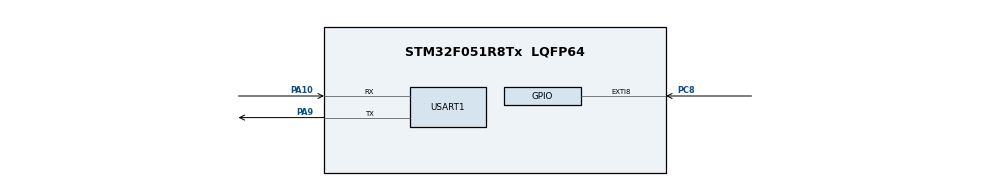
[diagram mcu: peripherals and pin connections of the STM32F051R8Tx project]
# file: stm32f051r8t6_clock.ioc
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Mcu.Family=STM32F0
Mcu.Name=STM32F051R8Tx
Mcu.Package=LQFP64
PA10.Mode=Asynchronous
PA10.Signal=USART1_RX
PA9.Mode=Asynchronous
PA9.Signal=USART1_TX
PC8.Signal=GPXTI8
ProjectManager.HeapSize=0x200
ProjectManager.StackSize=0x400
ProjectManager.TargetToolchain=MDK-ARM V5
RCC.AHBCLKDivider=RCC_SYSCLK_DIV2
RCC.AHBFreq_Value=8000000
RCC.APB1Freq_Value=8000000
RCC.APB1TimFreq_Value=8000000
RCC.HCLKFreq_Value=8000000
RCC.PLLMUL=RCC_PLL_MUL4
RCC.RCC_MCOSource=RCC_MCO1SOURCE_HSI
RCC.SYSCLKFreq_VALUE=16000000
RCC.SYSCLKSource=RCC_SYSCLKSOURCE_PLLCLK
RCC.Usart1ClockSelection=RCC_USART1CLKSOURCE_HSI
USART1.VirtualMode-Asynchronous=VM_ASYNC
board=custom

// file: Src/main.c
/**
  ******************************************************************************
  * @file           : main.c
  * @brief          : Main program body
  ******************************************************************************
  ** This notice applies to any and all portions of this file
  * that are not between comment pairs USER CODE BEGIN and
  * USER CODE END. Other portions of this file, whether
  * inserted by the user or by software development tools
  * are owned by their respective copyright owners.
  *
  * COPYRIGHT(c) 2018 STMicroelectronics
  *
  * Redistribution and use in source and binary forms, with or without modification,
  * are permitted provided that the following conditions are met:
  *   1. Redistributions of source code must retain the above copyright notice,
  *      this list of conditions and the following disclaimer.
  *   2. Redistributions in binary form must reproduce the above copyright notice,
  *      this list of conditions and the following disclaimer in the documentation
  *      and/or other materials provided with the distribution.
  *   3. Neither the name of STMicroelectronics nor the names of its contributors
  *      may be used to endorse or promote products derived from this software
  *      without specific prior written permission.
  *
  * THIS SOFTWARE IS PROVIDED BY THE COPYRIGHT HOLDERS AND CONTRIBUTORS "AS IS"
  * AND ANY EXPRESS OR IMPLIED WARRANTIES, INCLUDING, BUT NOT LIMITED TO, THE
  * IMPLIED WARRANTIES OF MERCHANTABILITY AND FITNESS FOR A PARTICULAR PURPOSE ARE
  * DISCLAIMED. IN NO EVENT SHALL THE COPYRIGHT HOLDER OR CONTRIBUTORS BE LIABLE
  * FOR ANY DIRECT, INDIRECT, INCIDENTAL, SPECIAL, EXEMPLARY, OR CONSEQUENTIAL
  * DAMAGES (INCLUDING, BUT NOT LIMITED TO, PROCUREMENT OF SUBSTITUTE GOODS OR
  * SERVICES; LOSS OF USE, DATA, OR PROFITS; OR BUSINESS INTERRUPTION) HOWEVER
  * CAUSED AND ON ANY THEORY OF LIABILITY, WHETHER IN CONTRACT, STRICT LIABILITY,
  * OR TORT (INCLUDING NEGLIGENCE OR OTHERWISE) ARISING IN ANY WAY OUT OF THE USE
  * OF THIS SOFTWARE, EVEN IF ADVISED OF THE POSSIBILITY OF SUCH DAMAGE.
  *
  ******************************************************************************
  */
#include "main.h"
#include "stm32f0xx_hal.h"

UART_HandleTypeDef huart1;

/* USER CODE BEGIN PV */
/* Private variables ---------------------------------------------------------*/

/* USER CODE END PV */

void SystemClock_Config(void);
static void MX_GPIO_Init(void);
static void MX_USART1_UART_Init(void);

/* USER CODE BEGIN PFP */
/* Private function prototypes -----------------------------------------------*/

/* USER CODE END PFP */

int main(void)
{

  /* MCU Configuration----------------------------------------------------------*/

  /* Reset of all peripherals, Initializes the Flash interface and the Systick. */
  HAL_Init();

  /* Configure the system clock */
  SystemClock_Config();

  /* Initialize all configured peripherals */
  MX_GPIO_Init();
  MX_USART1_UART_Init();

  /* Infinite loop */
  while (1)
  {

  }

}

void SystemClock_Config(void)
{

  RCC_OscInitTypeDef RCC_OscInitStruct;
  RCC_ClkInitTypeDef RCC_ClkInitStruct;
  RCC_PeriphCLKInitTypeDef PeriphClkInit;

    /**Initializes the CPU, AHB and APB busses clocks
    */
  RCC_OscInitStruct.OscillatorType = RCC_OSCILLATORTYPE_HSI;
  RCC_OscInitStruct.HSIState = RCC_HSI_ON;
  RCC_OscInitStruct.HSICalibrationValue = 16;
  RCC_OscInitStruct.PLL.PLLState = RCC_PLL_NONE;
  if (HAL_RCC_OscConfig(&RCC_OscInitStruct) != HAL_OK)
  {
    _Error_Handler(__FILE__, __LINE__);
  }

    /**Initializes the CPU, AHB and APB busses clocks
    */
  RCC_ClkInitStruct.ClockType = RCC_CLOCKTYPE_HCLK|RCC_CLOCKTYPE_SYSCLK
                              |RCC_CLOCKTYPE_PCLK1;
  RCC_ClkInitStruct.SYSCLKSource = RCC_SYSCLKSOURCE_HSI;
  RCC_ClkInitStruct.AHBCLKDivider = RCC_SYSCLK_DIV1;
  RCC_ClkInitStruct.APB1CLKDivider = RCC_HCLK_DIV1;

  if (HAL_RCC_ClockConfig(&RCC_ClkInitStruct, FLASH_LATENCY_0) != HAL_OK)
  {
    _Error_Handler(__FILE__, __LINE__);
  }

  PeriphClkInit.PeriphClockSelection = RCC_PERIPHCLK_USART1;
  PeriphClkInit.Usart1ClockSelection = RCC_USART1CLKSOURCE_PCLK1;
  if (HAL_RCCEx_PeriphCLKConfig(&PeriphClkInit) != HAL_OK)
  {
    _Error_Handler(__FILE__, __LINE__);
  }

    /**Configure the Systick interrupt time
    */
  HAL_SYSTICK_Config(HAL_RCC_GetHCLKFreq()/1000);

    /**Configure the Systick
    */
  HAL_SYSTICK_CLKSourceConfig(SYSTICK_CLKSOURCE_HCLK);

  /* SysTick_IRQn interrupt configuration */
  HAL_NVIC_SetPriority(SysTick_IRQn, 0, 0);
}

/* USART1 init function */
static void MX_USART1_UART_Init(void)
{

  huart1.Instance = USART1;
  huart1.Init.BaudRate = 38400;
  huart1.Init.WordLength = UART_WORDLENGTH_8B;
  huart1.Init.StopBits = UART_STOPBITS_1;
  huart1.Init.Parity = UART_PARITY_NONE;
  huart1.Init.Mode = UART_MODE_TX_RX;
  huart1.Init.HwFlowCtl = UART_HWCONTROL_NONE;
  huart1.Init.OverSampling = UART_OVERSAMPLING_16;
  huart1.Init.OneBitSampling = UART_ONE_BIT_SAMPLE_DISABLE;
  huart1.AdvancedInit.AdvFeatureInit = UART_ADVFEATURE_NO_INIT;
  if (HAL_UART_Init(&huart1) != HAL_OK)
  {
    _Error_Handler(__FILE__, __LINE__);
  }

}

/** Configure pins as
        * Analog
        * Input
        * Output
        * EVENT_OUT
        * EXTI
*/
static void MX_GPIO_Init(void)
{

  GPIO_InitTypeDef GPIO_InitStruct;

  /* GPIO Ports Clock Enable */
  __HAL_RCC_GPIOC_CLK_ENABLE();
  __HAL_RCC_GPIOA_CLK_ENABLE();

  /*Configure GPIO pin : PC8 */
  GPIO_InitStruct.Pin = GPIO_PIN_8;
  GPIO_InitStruct.Mode = GPIO_MODE_IT_RISING;
  GPIO_InitStruct.Pull = GPIO_NOPULL;
  HAL_GPIO_Init(GPIOC, &GPIO_InitStruct);

}

void _Error_Handler(char *file, int line)
{
  while(1)
  {
  }
}

/************************ (C) COPYRIGHT STMicroelectronics *****END OF FILE****/
